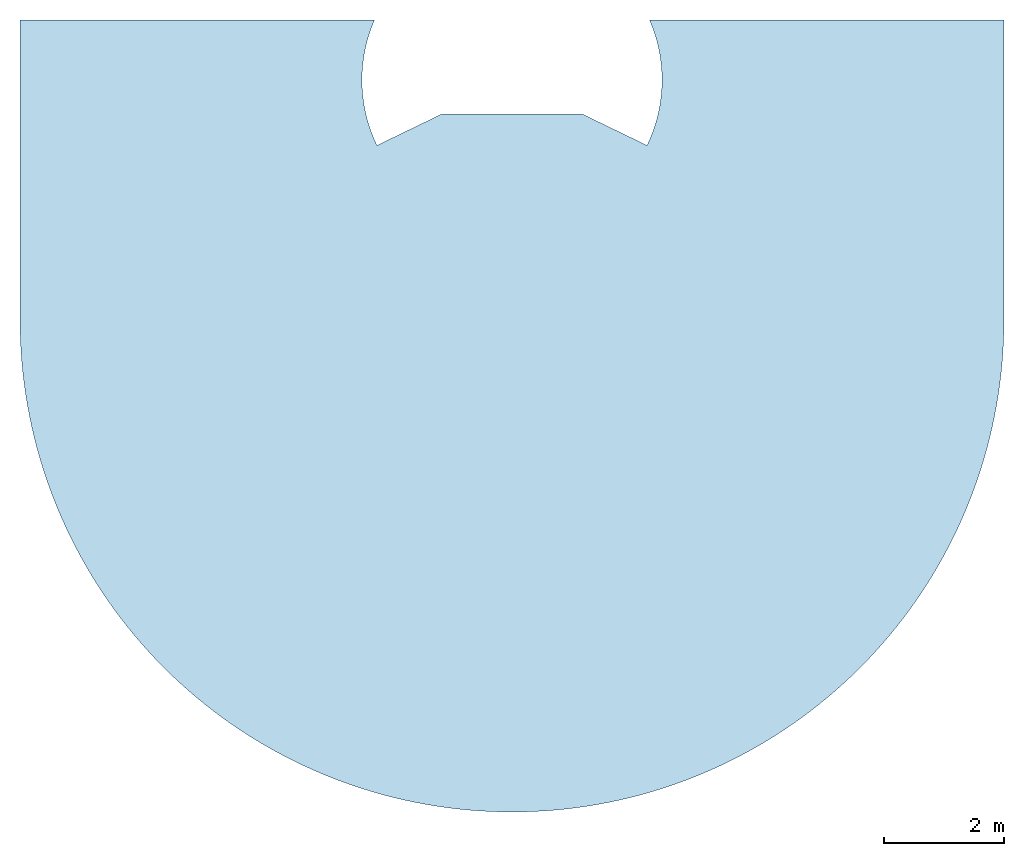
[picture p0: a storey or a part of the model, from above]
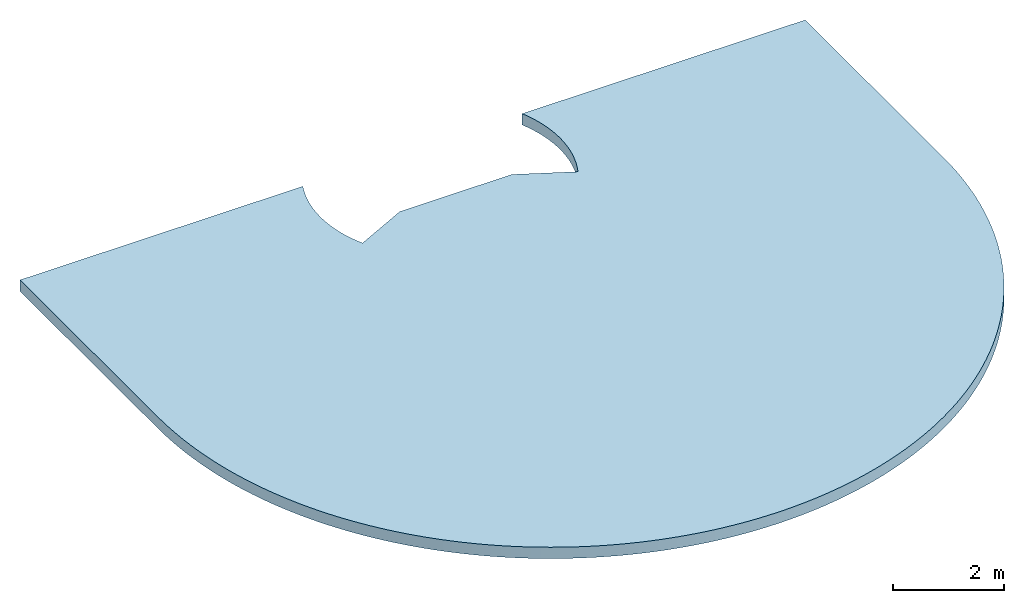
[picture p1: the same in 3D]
Properties of the parts of a building model (IFC4)

# File
Description: ViewDefinition [Design_Transfer_View, QuantityTakeOffAddOnView, SpaceBoundary2ndLevelAddOnView], ExchangeRequirement [Architecture], Option [Elements to export: Visible elements (on all stories)], Option [Partial Structure Display: Entire Model], Option [IFC Domain: All], Option [Structural Function: All Elements], Option [Convert Grid elements: On], Option [Convert IFC Annotations and Archicad 2D elements: Off], Option [Convert 2D symbols of Doors and Windows: Off], Option [Export geometries that Participates in Collision Detection only: Off], Option [Split complex elements: Off], Option [Material Preservation: Explode where necessary], Option [Elements in Solid Element Operations: Extruded/revolved], Option [Elements with junctions: Extruded/revolved without junctions], Option [IFC Model position: Survey Point and Project Origin], Option [Curtain Wall export mode: Container Element], Option [Railing export mode: Single Element], Option [Stair export mode: Container Element], Option [Properties To Export: All properties], Option [Space containment: On], Option [IFC Domain For Space Containment: All], Option [Geometry to type objects: Off], Option [Element Properties: Off], Option [Building Material Properties: Off], Option [Element Parameters: Off], Option [Component Parameters: Off], Option [IFC Base Quantities: On], Option [Door Window Parameters: On], Option [IFC Space boundaries: On], Option [Archicad Zone Categories as IFC Space classification data: Off], Option [Element Classifications: Off]
File name: C:\Users\micel\OneDrive\Dokumenty\ŠKOLA\!!4.LS!!\BAKALÁŘKA\Publikace\Nová složka\_LES24-PST-01-M3-Stropni_deska_nad_1NP.ifc
Time: 2024-05-21T14:06:41
Author: Architect
Organization: Building Designer Office
Written by: DDS_IFC v3.0
Made in: IFC file generated by Graphisoft Archicad 27.0.0 CZE FULL Windows version (IFC add-on version: 3001 CZE FULL).
Authorization: The authorising person

# IfcProject, Univerzitní lezecké centrum
Description: BIM projekt - bakalářská práce

# IfcSite, Exteriér
RefLatitude: 50, 1, 18, 339575; RefLongitude: 15, 46, 11, 568244; RefElevation: 221783 mm
Qto_SiteBaseQuantities - GrossPerimeter: 0 mm; GrossArea: 3562 m2

# IfcBuilding, Univerzitní lezecké centrum
Qto_BuildingBaseQuantities - GrossFloorArea: 0 m2

# IfcBuildingStorey, 2.NP
In: Univerzitní lezecké centrum
Elevation: 3200 mm
Qto_BuildingStoreyBaseQuantities - NetHeight: 3200 mm; GrossHeight: 3200 mm; GrossFloorArea: 0 m2

# IfcSlab: Beton vyztužený stropy 250, D03
In: 2.NP
Type - PredefinedType: FLOOR
Material: Beton vyztužený stropy 250 mm
Pset_SlabCommon - Status: EXISTING; LoadBearing: yes
Pset_ManufacturerOccurrence - AcquisitionDate: DD.MM.RRRR
Qto_SlabBaseQuantities - Width: 250 mm; Perimeter: 56630.9 mm; GrossArea: 179.238 m2; NetArea: 179.238 m2; GrossVolume: 44.8094 m3; NetVolume: 44.8094 m3; Beton vyztužený stropy, Width: 250 mm
